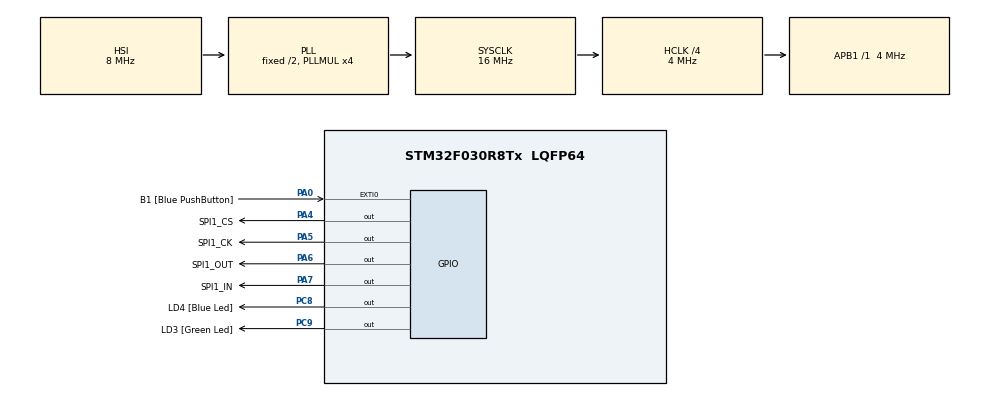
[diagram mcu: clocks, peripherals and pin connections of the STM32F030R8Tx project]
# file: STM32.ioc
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Mcu.Family=STM32F0
Mcu.Name=STM32F030R8Tx
Mcu.Package=LQFP64
PA0.GPIO_Label=B1 [Blue PushButton]
PA0.GPIO_ModeDefaultEXTI=GPIO_MODE_EVT_RISING
PA0.GPIO_PuPd=GPIO_NOPULL
PA0.Signal=GPXTI0
PA13.GPIO_Label=SWDIO
PA13.Mode=Serial-WireDebug
PA13.Signal=SYS_SWDIO
PA14.GPIO_Label=SWCLK
PA14.Mode=Serial-WireDebug
PA14.Signal=SYS_SWCLK
PA4.GPIO_Label=SPI1_CS
PA4.GPIO_ModeDefaultOutputPP=GPIO_MODE_OUTPUT_PP
PA4.GPIO_PuPd=GPIO_PULLUP
PA4.GPIO_Speed=GPIO_SPEED_LOW
PA4.Signal=GPIO_Output
PA5.GPIO_Label=SPI1_CK
PA5.GPIO_ModeDefaultOutputPP=GPIO_MODE_OUTPUT_PP
PA5.GPIO_PuPd=GPIO_PULLUP
PA5.GPIO_Speed=GPIO_SPEED_LOW
PA5.Signal=GPIO_Output
PA6.GPIO_Label=SPI1_OUT
PA6.GPIO_ModeDefaultOutputPP=GPIO_MODE_OUTPUT_PP
PA6.GPIO_PuPd=GPIO_PULLUP
PA6.GPIO_Speed=GPIO_SPEED_LOW
PA6.Signal=GPIO_Output
PA7.GPIO_Label=SPI1_IN
PA7.GPIO_ModeDefaultOutputPP=GPIO_MODE_OUTPUT_PP
PA7.GPIO_PuPd=GPIO_PULLUP
PA7.GPIO_Speed=GPIO_SPEED_LOW
PA7.Signal=GPIO_Output
PC8.GPIO_Label=LD4 [Blue Led]
PC8.GPIO_ModeDefaultOutputPP=GPIO_MODE_OUTPUT_PP
PC8.GPIO_PuPd=GPIO_NOPULL
PC8.GPIO_Speed=GPIO_SPEED_LOW
PC8.Signal=GPIO_Output
PC9.GPIO_Label=LD3 [Green Led]
PC9.GPIO_ModeDefaultOutputPP=GPIO_MODE_OUTPUT_PP
PC9.GPIO_PuPd=GPIO_NOPULL
PC9.GPIO_Speed=GPIO_SPEED_LOW
PC9.Signal=GPIO_Output
ProjectManager.TargetToolchain=MDK-ARM V5
RCC.AHBCLKDivider=RCC_SYSCLK_DIV4
RCC.AHBFreq_Value=4000000
RCC.APB1Freq_Value=4000000
RCC.APB1TimFreq_Value=4000000
RCC.HCLKFreq_Value=4000000
RCC.PLLMUL=RCC_PLL_MUL4
RCC.SYSCLKFreq_VALUE=16000000
RCC.SYSCLKSource=RCC_SYSCLKSOURCE_PLLCLK
board=STM32F0308-DISCO

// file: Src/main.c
/**
  ******************************************************************************
  * File Name          : main.c
  * Description        : Main program body
  ******************************************************************************
  *
  * COPYRIGHT(c) 2016 STMicroelectronics
  *
  * Redistribution and use in source and binary forms, with or without modification,
  * are permitted provided that the following conditions are met:
  *   1. Redistributions of source code must retain the above copyright notice,
  *      this list of conditions and the following disclaimer.
  *   2. Redistributions in binary form must reproduce the above copyright notice,
  *      this list of conditions and the following disclaimer in the documentation
  *      and/or other materials provided with the distribution.
  *   3. Neither the name of STMicroelectronics nor the names of its contributors
  *      may be used to endorse or promote products derived from this software
  *      without specific prior written permission.
  *
  * THIS SOFTWARE IS PROVIDED BY THE COPYRIGHT HOLDERS AND CONTRIBUTORS "AS IS"
  * AND ANY EXPRESS OR IMPLIED WARRANTIES, INCLUDING, BUT NOT LIMITED TO, THE
  * IMPLIED WARRANTIES OF MERCHANTABILITY AND FITNESS FOR A PARTICULAR PURPOSE ARE
  * DISCLAIMED. IN NO EVENT SHALL THE COPYRIGHT HOLDER OR CONTRIBUTORS BE LIABLE
  * FOR ANY DIRECT, INDIRECT, INCIDENTAL, SPECIAL, EXEMPLARY, OR CONSEQUENTIAL
  * DAMAGES (INCLUDING, BUT NOT LIMITED TO, PROCUREMENT OF SUBSTITUTE GOODS OR
  * SERVICES; LOSS OF USE, DATA, OR PROFITS; OR BUSINESS INTERRUPTION) HOWEVER
  * CAUSED AND ON ANY THEORY OF LIABILITY, WHETHER IN CONTRACT, STRICT LIABILITY,
  * OR TORT (INCLUDING NEGLIGENCE OR OTHERWISE) ARISING IN ANY WAY OUT OF THE USE
  * OF THIS SOFTWARE, EVEN IF ADVISED OF THE POSSIBILITY OF SUCH DAMAGE.
  *
  ******************************************************************************
  */
#include <string.h>
#include "stm32f0xx_hal.h"
//#include "SD_routines.h"
#include "diskio.h"
#include "ff.h"

/* USER CODE BEGIN PV */
/* Private variables ---------------------------------------------------------*/

/* USER CODE END PV */

void SystemClock_Config(void);
static void MX_GPIO_Init(void);

/* USER CODE BEGIN PFP */
/* Private function prototypes -----------------------------------------------*/

/* USER CODE END PFP */

/* USER CODE BEGIN 0 */
void delaymain(uint32_t x){while(x--);}
uint8_t buffer[512];
uint8_t mytext[16] = "hello world";
// unsigned char temp[512];
uint8_t status =1;
uint16_t timeout = 0;
uint16_t cnt = 32;
uint8_t *ptr,cntr,cntr1,cntr2,cntr3,cntr4,error;
unsigned int ret;
uint8_t chck,x;
FATFS FatFs;		/* FatFs work area needed for each volume */
FIL fp;			/* File object needed for each open file */

UINT bw;

void block_read(void);

/* USER CODE END 0 */

int main(void)
{

  /* MCU Configuration----------------------------------------------------------*/

  /* Reset of all peripherals, Initializes the Flash interface and the Systick. */
  HAL_Init();

  /* Configure the system clock */
  SystemClock_Config();

  /* Initialize all configured peripherals */
  MX_GPIO_Init();

	delaymain(500000);delaymain(5000000);
	cntr++;
  /* USER CODE BEGIN 2 */
	cntr1 = f_mount(&FatFs, "", 0);		/* Give a work area to the default drive */
	cntr++;
	cntr2 = f_open(&fp, "newfile.txt", FA_WRITE | FA_CREATE_ALWAYS);/* Create a file */
	cntr++;
	cntr3 =	f_write(&fp, "It works!\r\n", 11, &bw);	/* Write data to the file */
	cntr++;
	cntr4 =	f_close(&fp);								/* Close the file */
	cntr++;
//		if (bw == 11) {		/* Lights green LED if data written well */
//			DDRB |= 0x10; PORTB |= 0x10;	/* Set PB4 high */
//		}
//	}

	while(1);
}

/** System Clock Configuration
*/
void SystemClock_Config(void)
{

  RCC_OscInitTypeDef RCC_OscInitStruct;
  RCC_ClkInitTypeDef RCC_ClkInitStruct;

  RCC_OscInitStruct.OscillatorType = RCC_OSCILLATORTYPE_HSI;
  RCC_OscInitStruct.HSIState = RCC_HSI_ON;
  RCC_OscInitStruct.HSICalibrationValue = 16;
  RCC_OscInitStruct.PLL.PLLState = RCC_PLL_ON;
  RCC_OscInitStruct.PLL.PLLSource = RCC_PLLSOURCE_HSI;
  RCC_OscInitStruct.PLL.PLLMUL = RCC_PLL_MUL4;
  RCC_OscInitStruct.PLL.PREDIV = RCC_PREDIV_DIV1;
  HAL_RCC_OscConfig(&RCC_OscInitStruct);

  RCC_ClkInitStruct.ClockType = RCC_CLOCKTYPE_HCLK|RCC_CLOCKTYPE_SYSCLK;
  RCC_ClkInitStruct.SYSCLKSource = RCC_SYSCLKSOURCE_PLLCLK;
  RCC_ClkInitStruct.AHBCLKDivider = RCC_SYSCLK_DIV4;
  RCC_ClkInitStruct.APB1CLKDivider = RCC_HCLK_DIV1;
  HAL_RCC_ClockConfig(&RCC_ClkInitStruct, FLASH_LATENCY_0);

  HAL_SYSTICK_Config(HAL_RCC_GetHCLKFreq()/1000);

  HAL_SYSTICK_CLKSourceConfig(SYSTICK_CLKSOURCE_HCLK);

}

/** Configure pins as
        * Analog
        * Input
        * Output
        * EVENT_OUT
        * EXTI
*/
void MX_GPIO_Init(void)
{

  GPIO_InitTypeDef GPIO_InitStruct;

  /* GPIO Ports Clock Enable */
  __GPIOA_CLK_ENABLE();
  __GPIOC_CLK_ENABLE();

	/*Configure GPIO pins : PC0 PC1 PC3 */
  GPIO_InitStruct.Pin = GPIO_PIN_0|GPIO_PIN_1|GPIO_PIN_3;
  GPIO_InitStruct.Mode = GPIO_MODE_OUTPUT_PP;
  GPIO_InitStruct.Pull = GPIO_PULLUP;
  GPIO_InitStruct.Speed = GPIO_SPEED_LOW;
  HAL_GPIO_Init(GPIOC, &GPIO_InitStruct);

  /*Configure GPIO pin : PC2 */
  GPIO_InitStruct.Pin = GPIO_PIN_2;
  GPIO_InitStruct.Mode = GPIO_MODE_INPUT;
  GPIO_InitStruct.Pull = GPIO_PULLUP;
  HAL_GPIO_Init(GPIOC, &GPIO_InitStruct);

  /*Configure GPIO pin : PA0 */
  GPIO_InitStruct.Pin = GPIO_PIN_0;
  GPIO_InitStruct.Mode = GPIO_MODE_EVT_RISING;
  GPIO_InitStruct.Pull = GPIO_NOPULL;
  HAL_GPIO_Init(GPIOA, &GPIO_InitStruct);

  /*Configure GPIO pins : PA4 PA5 PA6 PA7 */
  GPIO_InitStruct.Pin = GPIO_PIN_4|GPIO_PIN_5|GPIO_PIN_6|GPIO_PIN_7;
  GPIO_InitStruct.Mode = GPIO_MODE_OUTPUT_PP;
  GPIO_InitStruct.Pull = GPIO_PULLUP;
  GPIO_InitStruct.Speed = GPIO_SPEED_LOW;
  HAL_GPIO_Init(GPIOA, &GPIO_InitStruct);

  /*Configure GPIO pins : PC8 PC9 */
  GPIO_InitStruct.Pin = GPIO_PIN_8|GPIO_PIN_9;
  GPIO_InitStruct.Mode = GPIO_MODE_OUTPUT_PP;
  GPIO_InitStruct.Pull = GPIO_NOPULL;
  GPIO_InitStruct.Speed = GPIO_SPEED_LOW;
  HAL_GPIO_Init(GPIOC, &GPIO_InitStruct);

}

/************************ (C) COPYRIGHT STMicroelectronics *****END OF FILE****/
